VERSION 5.7 ;
  NOWIREEXTENSIONATPIN ON ;
  DIVIDERCHAR "/" ;
  BUSBITCHARS "[]" ;
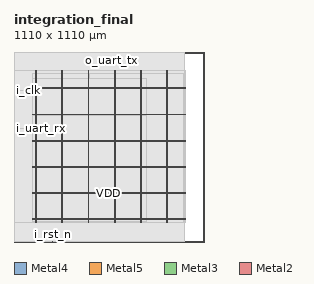
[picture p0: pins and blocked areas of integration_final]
MACRO integration_final
  CLASS BLOCK ;
  FOREIGN integration_final ;
  ORIGIN 0.000 0.000 ;
  SIZE 1110.000 BY 1110.000 ;
  PIN VDD
    DIRECTION INOUT ;
    USE POWER ;
    PORT
      LAYER Metal4 ;
        RECT 125.840 113.380 127.440 999.900 ;
    END
    PORT
      LAYER Metal4 ;
        RECT 279.440 113.380 281.040 999.900 ;
    END
    PORT
      LAYER Metal4 ;
        RECT 433.040 113.380 434.640 999.900 ;
    END
    PORT
      LAYER Metal4 ;
        RECT 586.640 113.380 588.240 999.900 ;
    END
    PORT
      LAYER Metal4 ;
        RECT 740.240 113.380 741.840 999.900 ;
    END
    PORT
      LAYER Metal4 ;
        RECT 893.840 113.380 895.440 999.900 ;
    END
    PORT
      LAYER Metal5 ;
        RECT 110.320 129.530 999.600 131.130 ;
    END
    PORT
      LAYER Metal5 ;
        RECT 110.320 282.710 999.600 284.310 ;
    END
    PORT
      LAYER Metal5 ;
        RECT 110.320 435.890 999.600 437.490 ;
    END
    PORT
      LAYER Metal5 ;
        RECT 110.320 589.070 999.600 590.670 ;
    END
    PORT
      LAYER Metal5 ;
        RECT 110.320 742.250 999.600 743.850 ;
    END
    PORT
      LAYER Metal5 ;
        RECT 110.320 895.430 999.600 897.030 ;
    END
  END VDD
  PIN VSS
    DIRECTION INOUT ;
    USE GROUND ;
    PORT
      LAYER Metal4 ;
        RECT 129.140 113.380 130.740 999.900 ;
    END
    PORT
      LAYER Metal4 ;
        RECT 282.740 113.380 284.340 999.900 ;
    END
    PORT
      LAYER Metal4 ;
        RECT 436.340 113.380 437.940 999.900 ;
    END
    PORT
      LAYER Metal4 ;
        RECT 589.940 113.380 591.540 999.900 ;
    END
    PORT
      LAYER Metal4 ;
        RECT 743.540 113.380 745.140 999.900 ;
    END
    PORT
      LAYER Metal4 ;
        RECT 897.140 113.380 898.740 999.900 ;
    END
    PORT
      LAYER Metal5 ;
        RECT 110.320 132.830 999.600 134.430 ;
    END
    PORT
      LAYER Metal5 ;
        RECT 110.320 286.010 999.600 287.610 ;
    END
    PORT
      LAYER Metal5 ;
        RECT 110.320 439.190 999.600 440.790 ;
    END
    PORT
      LAYER Metal5 ;
        RECT 110.320 592.370 999.600 593.970 ;
    END
    PORT
      LAYER Metal5 ;
        RECT 110.320 745.550 999.600 747.150 ;
    END
    PORT
      LAYER Metal5 ;
        RECT 110.320 898.730 999.600 900.330 ;
    END
  END VSS
  PIN i_clk
    DIRECTION INPUT ;
    USE SIGNAL ;
    ANTENNAGATEAREA 4.738000 ;
    PORT
      LAYER Metal3 ;
        RECT 0.000 883.680 0.560 884.240 ;
    END
  END i_clk
  PIN i_rst_n
    DIRECTION INPUT ;
    USE SIGNAL ;
    ANTENNAGATEAREA 11.020000 ;
    PORT
      LAYER Metal2 ;
        RECT 225.120 0.000 225.680 0.560 ;
    END
  END i_rst_n
  PIN i_uart_rx
    DIRECTION INPUT ;
    USE SIGNAL ;
    ANTENNAGATEAREA 0.396000 ;
    PORT
      LAYER Metal3 ;
        RECT 0.000 663.040 0.560 663.600 ;
    END
  END i_uart_rx
  PIN o_uart_tx
    DIRECTION OUTPUT ;
    USE SIGNAL ;
    ANTENNADIFFAREA 0.897600 ;
    PORT
      LAYER Metal2 ;
        RECT 571.200 1109.440 571.760 1110.000 ;
    END
  END o_uart_tx
  OBS
      LAYER Nwell ;
        RECT 109.890 113.250 1000.030 1000.030 ;
      LAYER Metal1 ;
        RECT 110.320 113.380 999.600 999.900 ;
      LAYER Metal2 ;
        RECT 0.140 1109.140 570.900 1109.440 ;
        RECT 572.060 1109.140 998.340 1109.440 ;
        RECT 0.140 0.860 998.340 1109.140 ;
        RECT 0.140 0.560 224.820 0.860 ;
        RECT 225.980 0.560 998.340 0.860 ;
      LAYER Metal3 ;
        RECT 0.090 884.540 998.390 999.740 ;
        RECT 0.860 883.380 998.390 884.540 ;
        RECT 0.090 663.900 998.390 883.380 ;
        RECT 0.860 662.740 998.390 663.900 ;
        RECT 0.090 112.700 998.390 662.740 ;
      LAYER Metal4 ;
        RECT 108.220 114.890 125.540 982.150 ;
        RECT 127.740 114.890 128.840 982.150 ;
        RECT 131.040 114.890 279.140 982.150 ;
        RECT 281.340 114.890 282.440 982.150 ;
        RECT 284.640 114.890 432.740 982.150 ;
        RECT 434.940 114.890 436.040 982.150 ;
        RECT 438.240 114.890 586.340 982.150 ;
        RECT 588.540 114.890 589.640 982.150 ;
        RECT 591.840 114.890 739.940 982.150 ;
        RECT 742.140 114.890 743.240 982.150 ;
        RECT 745.440 114.890 893.540 982.150 ;
        RECT 895.740 114.890 896.840 982.150 ;
        RECT 899.040 114.890 991.620 982.150 ;
      LAYER Metal5 ;
        RECT 108.140 900.930 774.980 954.670 ;
        RECT 108.140 898.130 109.720 900.930 ;
        RECT 108.140 897.630 774.980 898.130 ;
        RECT 108.140 894.830 109.720 897.630 ;
        RECT 108.140 747.750 774.980 894.830 ;
        RECT 108.140 744.950 109.720 747.750 ;
        RECT 108.140 744.450 774.980 744.950 ;
        RECT 108.140 741.650 109.720 744.450 ;
        RECT 108.140 594.570 774.980 741.650 ;
        RECT 108.140 591.770 109.720 594.570 ;
        RECT 108.140 591.270 774.980 591.770 ;
        RECT 108.140 588.470 109.720 591.270 ;
        RECT 108.140 441.390 774.980 588.470 ;
        RECT 108.140 438.590 109.720 441.390 ;
        RECT 108.140 438.090 774.980 438.590 ;
        RECT 108.140 435.290 109.720 438.090 ;
        RECT 108.140 288.210 774.980 435.290 ;
        RECT 108.140 285.410 109.720 288.210 ;
        RECT 108.140 284.910 774.980 285.410 ;
        RECT 108.140 282.110 109.720 284.910 ;
        RECT 108.140 135.030 774.980 282.110 ;
        RECT 108.140 132.230 109.720 135.030 ;
        RECT 108.140 131.730 774.980 132.230 ;
        RECT 108.140 128.930 109.720 131.730 ;
        RECT 108.140 118.130 774.980 128.930 ;
  END
END integration_final
END LIBRARY

